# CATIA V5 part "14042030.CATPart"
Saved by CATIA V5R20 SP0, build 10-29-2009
Part number: 14042030
Definition: NONE
Nomenclature: 14042030
Source: Unknown
Description: 14042030
Bounding box of the stored display mesh (mm): x -15 to 60, y -35 to 24.917, z -25.1 to 25.1
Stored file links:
  C:\Users\Utente\Desktop\IO LAVORO\3D X SITO CF\X SITO\PLASTICA\RF2\14042030.CATPart

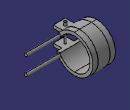
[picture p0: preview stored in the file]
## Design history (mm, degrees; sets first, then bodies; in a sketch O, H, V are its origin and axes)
Body1 "14042030" (main body)
  Solid1: solid without history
